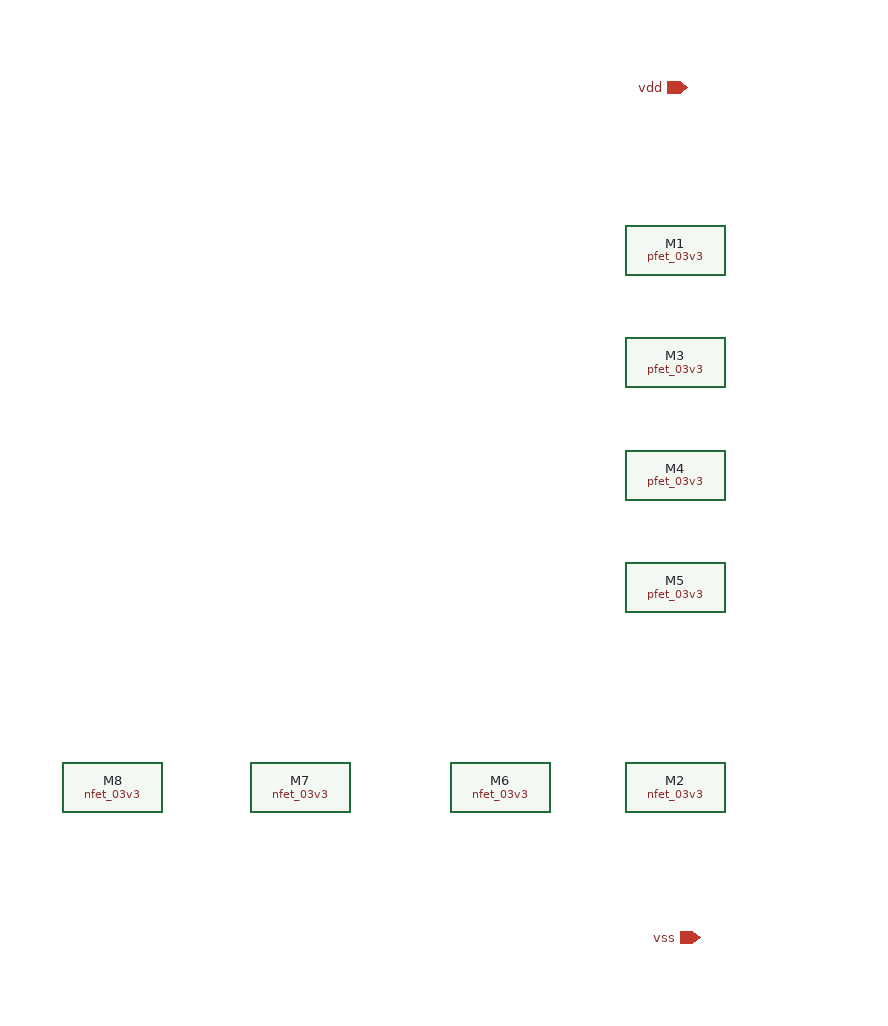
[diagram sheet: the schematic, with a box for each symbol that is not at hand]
v {xschem version=3.4.7 file_version=1.2}
G {}
K {}
V {}
S {}
E {}
C {title.sym} 40 0 0 0 {name=l1 author="The Digimons"}
C {symbols/pfet_03v3.sym} 750 -650 0 0 {name=M1
L=0.28u
W=0.22u
nf=1
m=1
ad="'int((nf+1)/2) * W/nf * 0.18u'"
pd="'2*int((nf+1)/2) * (W/nf + 0.18u)'"
as="'int((nf+2)/2) * W/nf * 0.18u'"
ps="'2*int((nf+2)/2) * (W/nf + 0.18u)'"
nrd="'0.18u / W'" nrs="'0.18u / W'"
sa=0 sb=0 sd=0
model=pfet_03v3
spiceprefix=X
}
C {symbols/nfet_03v3.sym} 750 -220 0 0 {name=M2
L=0.28u
W=0.22u
nf=1
m=1
ad="'int((nf+1)/2) * W/nf * 0.18u'"
pd="'2*int((nf+1)/2) * (W/nf + 0.18u)'"
as="'int((nf+2)/2) * W/nf * 0.18u'"
ps="'2*int((nf+2)/2) * (W/nf + 0.18u)'"
nrd="'0.18u / W'" nrs="'0.18u / W'"
sa=0 sb=0 sd=0
model=nfet_03v3
spiceprefix=X
}
C {symbols/pfet_03v3.sym} 750 -560 0 0 {name=M3
L=0.28u
W=0.22u
nf=1
m=1
ad="'int((nf+1)/2) * W/nf * 0.18u'"
pd="'2*int((nf+1)/2) * (W/nf + 0.18u)'"
as="'int((nf+2)/2) * W/nf * 0.18u'"
ps="'2*int((nf+2)/2) * (W/nf + 0.18u)'"
nrd="'0.18u / W'" nrs="'0.18u / W'"
sa=0 sb=0 sd=0
model=pfet_03v3
spiceprefix=X
}
C {symbols/pfet_03v3.sym} 750 -470 0 0 {name=M4
L=0.28u
W=0.22u
nf=1
m=1
ad="'int((nf+1)/2) * W/nf * 0.18u'"
pd="'2*int((nf+1)/2) * (W/nf + 0.18u)'"
as="'int((nf+2)/2) * W/nf * 0.18u'"
ps="'2*int((nf+2)/2) * (W/nf + 0.18u)'"
nrd="'0.18u / W'" nrs="'0.18u / W'"
sa=0 sb=0 sd=0
model=pfet_03v3
spiceprefix=X
}
C {symbols/pfet_03v3.sym} 750 -380 0 0 {name=M5
L=0.28u
W=0.22u
nf=1
m=1
ad="'int((nf+1)/2) * W/nf * 0.18u'"
pd="'2*int((nf+1)/2) * (W/nf + 0.18u)'"
as="'int((nf+2)/2) * W/nf * 0.18u'"
ps="'2*int((nf+2)/2) * (W/nf + 0.18u)'"
nrd="'0.18u / W'" nrs="'0.18u / W'"
sa=0 sb=0 sd=0
model=pfet_03v3
spiceprefix=X
}
C {symbols/nfet_03v3.sym} 610 -220 0 0 {name=M6
L=0.28u
W=0.22u
nf=1
m=1
ad="'int((nf+1)/2) * W/nf * 0.18u'"
pd="'2*int((nf+1)/2) * (W/nf + 0.18u)'"
as="'int((nf+2)/2) * W/nf * 0.18u'"
ps="'2*int((nf+2)/2) * (W/nf + 0.18u)'"
nrd="'0.18u / W'" nrs="'0.18u / W'"
sa=0 sb=0 sd=0
model=nfet_03v3
spiceprefix=X
}
C {symbols/nfet_03v3.sym} 450 -220 0 0 {name=M7
L=0.28u
W=0.22u
nf=1
m=1
ad="'int((nf+1)/2) * W/nf * 0.18u'"
pd="'2*int((nf+1)/2) * (W/nf + 0.18u)'"
as="'int((nf+2)/2) * W/nf * 0.18u'"
ps="'2*int((nf+2)/2) * (W/nf + 0.18u)'"
nrd="'0.18u / W'" nrs="'0.18u / W'"
sa=0 sb=0 sd=0
model=nfet_03v3
spiceprefix=X
}
C {symbols/nfet_03v3.sym} 300 -220 0 0 {name=M8
L=0.28u
W=0.22u
nf=1
m=1
ad="'int((nf+1)/2) * W/nf * 0.18u'"
pd="'2*int((nf+1)/2) * (W/nf + 0.18u)'"
as="'int((nf+2)/2) * W/nf * 0.18u'"
ps="'2*int((nf+2)/2) * (W/nf + 0.18u)'"
nrd="'0.18u / W'" nrs="'0.18u / W'"
sa=0 sb=0 sd=0
model=nfet_03v3
spiceprefix=X
}
C {iopin.sym} 760 -780 3 0 {name=p1 lab=vdd}
C {iopin.sym} 770 -100 1 0 {name=p2 lab=vss}
